###############################################################
#  Generated by:      Cadence Innovus 21.14-s109_1
#  OS:                Linux x86_64(Host ID caen-vnc-mi05.engin.umich.edu)
#  Generated on:      Thu Mar 30 18:29:03 2023
#  Design:            writeback_controller
#  Command:           write_lef_abstract /afs/umich.edu/class/eecs627/w23/groups/group4/CNN_LSTM/wb_controller/apr/wb_controller/data/writeback_controller.lef -specifyTopLayer 4 -stripePin -PGpinLayers 4
###############################################################

VERSION 5.8 ;

BUSBITCHARS "[]" ;
DIVIDERCHAR "/" ;

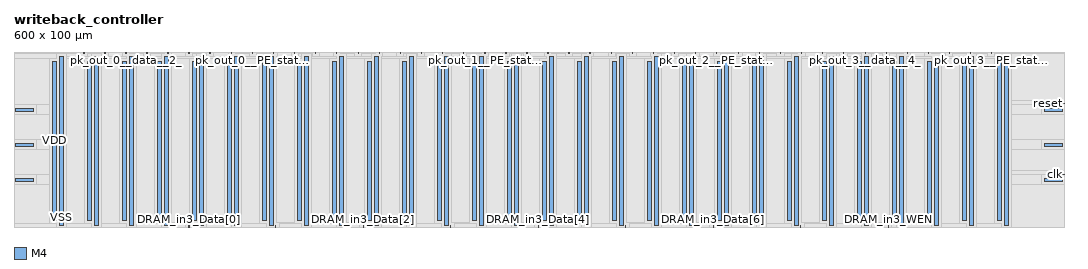
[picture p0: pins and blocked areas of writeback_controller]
MACRO writeback_controller
  CLASS BLOCK ;
  SIZE 600.000000 BY 100.000000 ;
  FOREIGN writeback_controller 0.000000 0.000000 ;
  ORIGIN 0 0 ;
  SYMMETRY X Y R90 ;
  PIN clk
    DIRECTION INPUT ;
    USE SIGNAL ;
    ANTENNAPARTIALMETALAREA 12.02 LAYER M4  ;
    ANTENNAPARTIALMETALSIDEAREA 0.1206 LAYER M4  ;
    ANTENNAMODEL OXIDE1 ;
    ANTENNAGATEAREA 1.2096 LAYER M4  ;
    ANTENNAMAXAREACAR 92.9835 LAYER M4  ;
    ANTENNAMAXSIDEAREACAR 0.93879 LAYER M4  ;
    ANTENNAMAXCUTCAR 2.38095 LAYER V4  ;
    PORT
      LAYER M4 ;
        RECT 599.400000 29.900000 600.000000 30.100000 ;
    END
  END clk
  PIN reset
    DIRECTION INPUT ;
    USE SIGNAL ;
    ANTENNAPARTIALMETALAREA 3.36 LAYER M4  ;
    ANTENNAPARTIALMETALSIDEAREA 0.0336 LAYER M4  ;
    ANTENNAMODEL OXIDE1 ;
    ANTENNAGATEAREA 0.2136 LAYER M4  ;
    ANTENNAMAXAREACAR 122.578 LAYER M4  ;
    ANTENNAMAXSIDEAREACAR 1.23081 LAYER M4  ;
    ANTENNAMAXCUTCAR 0.93633 LAYER V4  ;
    PORT
      LAYER M4 ;
        RECT 599.400000 70.300000 600.000000 70.500000 ;
    END
  END reset
  PIN DRAM_in3_WEN
    DIRECTION OUTPUT ;
    USE SIGNAL ;
    ANTENNADIFFAREA 2.112 LAYER M4  ;
    ANTENNAPARTIALMETALAREA 14.46 LAYER M4  ;
    ANTENNAPARTIALMETALSIDEAREA 0.1446 LAYER M4  ;
    PORT
      LAYER M4 ;
        RECT 499.500000 0.000000 499.700000 0.600000 ;
    END
  END DRAM_in3_WEN
  PIN DRAM_in3_Data[7]
    DIRECTION OUTPUT ;
    USE SIGNAL ;
    ANTENNADIFFAREA 3.348 LAYER M4  ;
    ANTENNAPARTIALMETALAREA 15.26 LAYER M4  ;
    ANTENNAPARTIALMETALSIDEAREA 0.1526 LAYER M4  ;
    PORT
      LAYER M4 ;
        RECT 449.500000 0.000000 449.700000 0.600000 ;
    END
  END DRAM_in3_Data[7]
  PIN DRAM_in3_Data[6]
    DIRECTION OUTPUT ;
    USE SIGNAL ;
    ANTENNADIFFAREA 3.348 LAYER M4  ;
    ANTENNAPARTIALMETALAREA 14.94 LAYER M4  ;
    ANTENNAPARTIALMETALSIDEAREA 0.1494 LAYER M4  ;
    PORT
      LAYER M4 ;
        RECT 399.500000 0.000000 399.700000 0.600000 ;
    END
  END DRAM_in3_Data[6]
  PIN DRAM_in3_Data[5]
    DIRECTION OUTPUT ;
    USE SIGNAL ;
    ANTENNADIFFAREA 2.112 LAYER M4  ;
    ANTENNAPARTIALMETALAREA 11.26 LAYER M4  ;
    ANTENNAPARTIALMETALSIDEAREA 0.1126 LAYER M4  ;
    PORT
      LAYER M4 ;
        RECT 349.500000 0.000000 349.700000 0.600000 ;
    END
  END DRAM_in3_Data[5]
  PIN DRAM_in3_Data[4]
    DIRECTION OUTPUT ;
    USE SIGNAL ;
    ANTENNADIFFAREA 2.112 LAYER M4  ;
    ANTENNAPARTIALMETALAREA 1.58 LAYER M4  ;
    ANTENNAPARTIALMETALSIDEAREA 0.0158 LAYER M4  ;
    PORT
      LAYER M4 ;
        RECT 299.500000 0.000000 299.700000 0.600000 ;
    END
  END DRAM_in3_Data[4]
  PIN DRAM_in3_Data[3]
    DIRECTION OUTPUT ;
    USE SIGNAL ;
    ANTENNADIFFAREA 2.112 LAYER M4  ;
    ANTENNAPARTIALMETALAREA 6.46 LAYER M4  ;
    ANTENNAPARTIALMETALSIDEAREA 0.0646 LAYER M4  ;
    PORT
      LAYER M4 ;
        RECT 249.500000 0.000000 249.700000 0.600000 ;
    END
  END DRAM_in3_Data[3]
  PIN DRAM_in3_Data[2]
    DIRECTION OUTPUT ;
    USE SIGNAL ;
    ANTENNADIFFAREA 2.112 LAYER M4  ;
    ANTENNAPARTIALMETALAREA 11.12 LAYER M4  ;
    ANTENNAPARTIALMETALSIDEAREA 0.1112 LAYER M4  ;
    PORT
      LAYER M4 ;
        RECT 199.500000 0.000000 199.700000 0.600000 ;
    END
  END DRAM_in3_Data[2]
  PIN DRAM_in3_Data[1]
    DIRECTION OUTPUT ;
    USE SIGNAL ;
    ANTENNADIFFAREA 2.112 LAYER M4  ;
    ANTENNAPARTIALMETALAREA 14.54 LAYER M4  ;
    ANTENNAPARTIALMETALSIDEAREA 0.1454 LAYER M4  ;
    PORT
      LAYER M4 ;
        RECT 149.500000 0.000000 149.700000 0.600000 ;
    END
  END DRAM_in3_Data[1]
  PIN DRAM_in3_Data[0]
    DIRECTION OUTPUT ;
    USE SIGNAL ;
    ANTENNADIFFAREA 2.112 LAYER M4  ;
    ANTENNAPARTIALMETALAREA 14.94 LAYER M4  ;
    ANTENNAPARTIALMETALSIDEAREA 0.1494 LAYER M4  ;
    PORT
      LAYER M4 ;
        RECT 99.900000 0.000000 100.100000 0.600000 ;
    END
  END DRAM_in3_Data[0]
  PIN pk_out_3__PE_state__2_
    DIRECTION INPUT ;
    USE SIGNAL ;
    ANTENNAPARTIALMETALAREA 2.3 LAYER M4  ;
    ANTENNAPARTIALMETALSIDEAREA 0.023 LAYER M4  ;
    ANTENNAMODEL OXIDE1 ;
    ANTENNAGATEAREA 0.0624 LAYER M4  ;
    ANTENNAMAXAREACAR 91.4599 LAYER M4  ;
    ANTENNAMAXSIDEAREACAR 0.930128 LAYER M4  ;
    ANTENNAMAXCUTCAR 3.20513 LAYER V4  ;
    PORT
      LAYER M4 ;
        RECT 558.300000 99.400000 558.500000 100.000000 ;
    END
  END pk_out_3__PE_state__2_
  PIN pk_out_3__PE_state__1_
    DIRECTION INPUT ;
    USE SIGNAL ;
    ANTENNAPARTIALMETALAREA 1.9 LAYER M4  ;
    ANTENNAPARTIALMETALSIDEAREA 0.019 LAYER M4  ;
    ANTENNAMODEL OXIDE1 ;
    ANTENNAGATEAREA 0.1632 LAYER M4  ;
    ANTENNAMAXAREACAR 21.9412 LAYER M4  ;
    ANTENNAMAXSIDEAREACAR 0.225613 LAYER M4  ;
    ANTENNAMAXCUTCAR 1.22549 LAYER V4  ;
    PORT
      LAYER M4 ;
        RECT 546.300000 99.400000 546.500000 100.000000 ;
    END
  END pk_out_3__PE_state__1_
  PIN pk_out_3__PE_state__0_
    DIRECTION INPUT ;
    USE SIGNAL ;
    ANTENNAPARTIALMETALAREA 2.06 LAYER M4  ;
    ANTENNAPARTIALMETALSIDEAREA 0.0206 LAYER M4  ;
    ANTENNAMODEL OXIDE1 ;
    ANTENNAGATEAREA 0.1632 LAYER M4  ;
    ANTENNAMAXAREACAR 26.7126 LAYER M4  ;
    ANTENNAMAXSIDEAREACAR 0.272794 LAYER M4  ;
    ANTENNAMAXCUTCAR 1.22549 LAYER V4  ;
    PORT
      LAYER M4 ;
        RECT 534.300000 99.400000 534.500000 100.000000 ;
    END
  END pk_out_3__PE_state__0_
  PIN pk_out_3__data__7_
    DIRECTION INPUT ;
    USE SIGNAL ;
    PORT
      LAYER M4 ;
        RECT 522.300000 99.400000 522.500000 100.000000 ;
    END
  END pk_out_3__data__7_
  PIN pk_out_3__data__6_
    DIRECTION INPUT ;
    USE SIGNAL ;
    PORT
      LAYER M4 ;
        RECT 510.300000 99.400000 510.500000 100.000000 ;
    END
  END pk_out_3__data__6_
  PIN pk_out_3__data__5_
    DIRECTION INPUT ;
    USE SIGNAL ;
    PORT
      LAYER M4 ;
        RECT 498.300000 99.400000 498.500000 100.000000 ;
    END
  END pk_out_3__data__5_
  PIN pk_out_3__data__4_
    DIRECTION INPUT ;
    USE SIGNAL ;
    PORT
      LAYER M4 ;
        RECT 486.300000 99.400000 486.500000 100.000000 ;
    END
  END pk_out_3__data__4_
  PIN pk_out_3__data__3_
    DIRECTION INPUT ;
    USE SIGNAL ;
    PORT
      LAYER M4 ;
        RECT 473.900000 99.400000 474.100000 100.000000 ;
    END
  END pk_out_3__data__3_
  PIN pk_out_3__data__2_
    DIRECTION INPUT ;
    USE SIGNAL ;
    PORT
      LAYER M4 ;
        RECT 461.900000 99.400000 462.100000 100.000000 ;
    END
  END pk_out_3__data__2_
  PIN pk_out_3__data__1_
    DIRECTION INPUT ;
    USE SIGNAL ;
    PORT
      LAYER M4 ;
        RECT 449.900000 99.400000 450.100000 100.000000 ;
    END
  END pk_out_3__data__1_
  PIN pk_out_3__data__0_
    DIRECTION INPUT ;
    USE SIGNAL ;
    PORT
      LAYER M4 ;
        RECT 437.900000 99.400000 438.100000 100.000000 ;
    END
  END pk_out_3__data__0_
  PIN pk_out_2__PE_state__2_
    DIRECTION INPUT ;
    USE SIGNAL ;
    ANTENNAPARTIALMETALAREA 2.54 LAYER M4  ;
    ANTENNAPARTIALMETALSIDEAREA 0.0254 LAYER M4  ;
    ANTENNAMODEL OXIDE1 ;
    ANTENNAGATEAREA 0.0624 LAYER M4  ;
    ANTENNAMAXAREACAR 105.562 LAYER M4  ;
    ANTENNAMAXSIDEAREACAR 1.07115 LAYER M4  ;
    ANTENNAMAXCUTCAR 3.20513 LAYER V4  ;
    PORT
      LAYER M4 ;
        RECT 425.900000 99.400000 426.100000 100.000000 ;
    END
  END pk_out_2__PE_state__2_
  PIN pk_out_2__PE_state__1_
    DIRECTION INPUT ;
    USE SIGNAL ;
    ANTENNAPARTIALMETALAREA 2.14 LAYER M4  ;
    ANTENNAPARTIALMETALSIDEAREA 0.0214 LAYER M4  ;
    ANTENNAMODEL OXIDE1 ;
    ANTENNAGATEAREA 0.1632 LAYER M4  ;
    ANTENNAMAXAREACAR 24.3922 LAYER M4  ;
    ANTENNAMAXSIDEAREACAR 0.250123 LAYER M4  ;
    ANTENNAMAXCUTCAR 1.22549 LAYER V4  ;
    PORT
      LAYER M4 ;
        RECT 413.900000 99.400000 414.100000 100.000000 ;
    END
  END pk_out_2__PE_state__1_
  PIN pk_out_2__PE_state__0_
    DIRECTION INPUT ;
    USE SIGNAL ;
    ANTENNAPARTIALMETALAREA 2.78 LAYER M4  ;
    ANTENNAPARTIALMETALSIDEAREA 0.0278 LAYER M4  ;
    ANTENNAMODEL OXIDE1 ;
    ANTENNAGATEAREA 0.1632 LAYER M4  ;
    ANTENNAMAXAREACAR 27.2028 LAYER M4  ;
    ANTENNAMAXSIDEAREACAR 0.277696 LAYER M4  ;
    ANTENNAMAXCUTCAR 1.22549 LAYER V4  ;
    PORT
      LAYER M4 ;
        RECT 401.500000 99.400000 401.700000 100.000000 ;
    END
  END pk_out_2__PE_state__0_
  PIN pk_out_2__data__7_
    DIRECTION INPUT ;
    USE SIGNAL ;
    PORT
      LAYER M4 ;
        RECT 389.500000 99.400000 389.700000 100.000000 ;
    END
  END pk_out_2__data__7_
  PIN pk_out_2__data__6_
    DIRECTION INPUT ;
    USE SIGNAL ;
    PORT
      LAYER M4 ;
        RECT 377.500000 99.400000 377.700000 100.000000 ;
    END
  END pk_out_2__data__6_
  PIN pk_out_2__data__5_
    DIRECTION INPUT ;
    USE SIGNAL ;
    PORT
      LAYER M4 ;
        RECT 365.500000 99.400000 365.700000 100.000000 ;
    END
  END pk_out_2__data__5_
  PIN pk_out_2__data__4_
    DIRECTION INPUT ;
    USE SIGNAL ;
    PORT
      LAYER M4 ;
        RECT 353.500000 99.400000 353.700000 100.000000 ;
    END
  END pk_out_2__data__4_
  PIN pk_out_2__data__3_
    DIRECTION INPUT ;
    USE SIGNAL ;
    PORT
      LAYER M4 ;
        RECT 341.500000 99.400000 341.700000 100.000000 ;
    END
  END pk_out_2__data__3_
  PIN pk_out_2__data__2_
    DIRECTION INPUT ;
    USE SIGNAL ;
    PORT
      LAYER M4 ;
        RECT 329.100000 99.400000 329.300000 100.000000 ;
    END
  END pk_out_2__data__2_
  PIN pk_out_2__data__1_
    DIRECTION INPUT ;
    USE SIGNAL ;
    PORT
      LAYER M4 ;
        RECT 317.100000 99.400000 317.300000 100.000000 ;
    END
  END pk_out_2__data__1_
  PIN pk_out_2__data__0_
    DIRECTION INPUT ;
    USE SIGNAL ;
    PORT
      LAYER M4 ;
        RECT 305.100000 99.400000 305.300000 100.000000 ;
    END
  END pk_out_2__data__0_
  PIN pk_out_1__PE_state__2_
    DIRECTION INPUT ;
    USE SIGNAL ;
    ANTENNAPARTIALMETALAREA 2.3 LAYER M4  ;
    ANTENNAPARTIALMETALSIDEAREA 0.023 LAYER M4  ;
    ANTENNAMODEL OXIDE1 ;
    ANTENNAGATEAREA 0.0624 LAYER M4  ;
    ANTENNAMAXAREACAR 69.6651 LAYER M4  ;
    ANTENNAMAXSIDEAREACAR 0.712179 LAYER M4  ;
    ANTENNAMAXCUTCAR 3.20513 LAYER V4  ;
    PORT
      LAYER M4 ;
        RECT 293.100000 99.400000 293.300000 100.000000 ;
    END
  END pk_out_1__PE_state__2_
  PIN pk_out_1__PE_state__1_
    DIRECTION INPUT ;
    USE SIGNAL ;
    ANTENNAPARTIALMETALAREA 2.22 LAYER M4  ;
    ANTENNAPARTIALMETALSIDEAREA 0.0222 LAYER M4  ;
    ANTENNAMODEL OXIDE1 ;
    ANTENNAGATEAREA 0.1632 LAYER M4  ;
    ANTENNAMAXAREACAR 21.451 LAYER M4  ;
    ANTENNAMAXSIDEAREACAR 0.220711 LAYER M4  ;
    ANTENNAMAXCUTCAR 1.22549 LAYER V4  ;
    PORT
      LAYER M4 ;
        RECT 281.100000 99.400000 281.300000 100.000000 ;
    END
  END pk_out_1__PE_state__1_
  PIN pk_out_1__PE_state__0_
    DIRECTION INPUT ;
    USE SIGNAL ;
    ANTENNAPARTIALMETALAREA 2.3 LAYER M4  ;
    ANTENNAPARTIALMETALSIDEAREA 0.023 LAYER M4  ;
    ANTENNAMODEL OXIDE1 ;
    ANTENNAGATEAREA 0.1632 LAYER M4  ;
    ANTENNAMAXAREACAR 34.5558 LAYER M4  ;
    ANTENNAMAXSIDEAREACAR 0.351225 LAYER M4  ;
    ANTENNAMAXCUTCAR 1.22549 LAYER V4  ;
    PORT
      LAYER M4 ;
        RECT 269.100000 99.400000 269.300000 100.000000 ;
    END
  END pk_out_1__PE_state__0_
  PIN pk_out_1__data__7_
    DIRECTION INPUT ;
    USE SIGNAL ;
    ANTENNAPARTIALMETALAREA 2.26 LAYER M4  ;
    ANTENNAPARTIALMETALSIDEAREA 0.023 LAYER M4  ;
    ANTENNAMODEL OXIDE1 ;
    ANTENNAGATEAREA 0.0888 LAYER M4  ;
    ANTENNAMAXAREACAR 38.7072 LAYER M4  ;
    ANTENNAMAXSIDEAREACAR 0.403829 LAYER M4  ;
    ANTENNAMAXCUTCAR 2.25225 LAYER V4  ;
    PORT
      LAYER M4 ;
        RECT 256.700000 99.400000 256.900000 100.000000 ;
    END
  END pk_out_1__data__7_
  PIN pk_out_1__data__6_
    DIRECTION INPUT ;
    USE SIGNAL ;
    ANTENNAPARTIALMETALAREA 2.34 LAYER M4  ;
    ANTENNAPARTIALMETALSIDEAREA 0.0238 LAYER M4  ;
    ANTENNAMODEL OXIDE1 ;
    ANTENNAGATEAREA 0.0888 LAYER M4  ;
    ANTENNAMAXAREACAR 43.2117 LAYER M4  ;
    ANTENNAMAXSIDEAREACAR 0.448874 LAYER M4  ;
    ANTENNAMAXCUTCAR 2.25225 LAYER V4  ;
    PORT
      LAYER M4 ;
        RECT 244.700000 99.400000 244.900000 100.000000 ;
    END
  END pk_out_1__data__6_
  PIN pk_out_1__data__5_
    DIRECTION INPUT ;
    USE SIGNAL ;
    ANTENNAPARTIALMETALAREA 2.34 LAYER M4  ;
    ANTENNAPARTIALMETALSIDEAREA 0.0238 LAYER M4  ;
    ANTENNAMODEL OXIDE1 ;
    ANTENNAGATEAREA 0.0888 LAYER M4  ;
    ANTENNAMAXAREACAR 41.4099 LAYER M4  ;
    ANTENNAMAXSIDEAREACAR 0.430856 LAYER M4  ;
    ANTENNAMAXCUTCAR 2.25225 LAYER V4  ;
    PORT
      LAYER M4 ;
        RECT 232.700000 99.400000 232.900000 100.000000 ;
    END
  END pk_out_1__data__5_
  PIN pk_out_1__data__4_
    DIRECTION INPUT ;
    USE SIGNAL ;
    ANTENNAPARTIALMETALAREA 2.26 LAYER M4  ;
    ANTENNAPARTIALMETALSIDEAREA 0.023 LAYER M4  ;
    ANTENNAMODEL OXIDE1 ;
    ANTENNAGATEAREA 0.0888 LAYER M4  ;
    ANTENNAMAXAREACAR 41.4099 LAYER M4  ;
    ANTENNAMAXSIDEAREACAR 0.430856 LAYER M4  ;
    ANTENNAMAXCUTCAR 2.25225 LAYER V4  ;
    PORT
      LAYER M4 ;
        RECT 220.700000 99.400000 220.900000 100.000000 ;
    END
  END pk_out_1__data__4_
  PIN pk_out_1__data__3_
    DIRECTION INPUT ;
    USE SIGNAL ;
    ANTENNAPARTIALMETALAREA 2.42 LAYER M4  ;
    ANTENNAPARTIALMETALSIDEAREA 0.0246 LAYER M4  ;
    ANTENNAMODEL OXIDE1 ;
    ANTENNAGATEAREA 0.0888 LAYER M4  ;
    ANTENNAMAXAREACAR 42.3108 LAYER M4  ;
    ANTENNAMAXSIDEAREACAR 0.439865 LAYER M4  ;
    ANTENNAMAXCUTCAR 2.25225 LAYER V4  ;
    PORT
      LAYER M4 ;
        RECT 208.700000 99.400000 208.900000 100.000000 ;
    END
  END pk_out_1__data__3_
  PIN pk_out_1__data__2_
    DIRECTION INPUT ;
    USE SIGNAL ;
    ANTENNAPARTIALMETALAREA 1.62 LAYER M4  ;
    ANTENNAPARTIALMETALSIDEAREA 0.0166 LAYER M4  ;
    ANTENNAMODEL OXIDE1 ;
    ANTENNAGATEAREA 0.0888 LAYER M4  ;
    ANTENNAMAXAREACAR 31.5 LAYER M4  ;
    ANTENNAMAXSIDEAREACAR 0.331757 LAYER M4  ;
    ANTENNAMAXCUTCAR 2.25225 LAYER V4  ;
    PORT
      LAYER M4 ;
        RECT 196.700000 99.400000 196.900000 100.000000 ;
    END
  END pk_out_1__data__2_
  PIN pk_out_1__data__1_
    DIRECTION INPUT ;
    USE SIGNAL ;
    ANTENNAPARTIALMETALAREA 3.06 LAYER M4  ;
    ANTENNAPARTIALMETALSIDEAREA 0.031 LAYER M4  ;
    ANTENNAMODEL OXIDE1 ;
    ANTENNAGATEAREA 0.0888 LAYER M4  ;
    ANTENNAMAXAREACAR 67.536 LAYER M4  ;
    ANTENNAMAXSIDEAREACAR 0.692117 LAYER M4  ;
    ANTENNAMAXCUTCAR 2.25225 LAYER V4  ;
    PORT
      LAYER M4 ;
        RECT 184.300000 99.400000 184.500000 100.000000 ;
    END
  END pk_out_1__data__1_
  PIN pk_out_1__data__0_
    DIRECTION INPUT ;
    USE SIGNAL ;
    ANTENNAPARTIALMETALAREA 2.34 LAYER M4  ;
    ANTENNAPARTIALMETALSIDEAREA 0.0238 LAYER M4  ;
    ANTENNAMODEL OXIDE1 ;
    ANTENNAGATEAREA 0.0888 LAYER M4  ;
    ANTENNAMAXAREACAR 31.5 LAYER M4  ;
    ANTENNAMAXSIDEAREACAR 0.331757 LAYER M4  ;
    ANTENNAMAXCUTCAR 2.25225 LAYER V4  ;
    PORT
      LAYER M4 ;
        RECT 172.300000 99.400000 172.500000 100.000000 ;
    END
  END pk_out_1__data__0_
  PIN pk_out_0__PE_state__2_
    DIRECTION INPUT ;
    USE SIGNAL ;
    ANTENNAPARTIALMETALAREA 2.14 LAYER M4  ;
    ANTENNAPARTIALMETALSIDEAREA 0.0214 LAYER M4  ;
    ANTENNAMODEL OXIDE1 ;
    ANTENNAGATEAREA 0.6168 LAYER M4  ;
    ANTENNAMAXAREACAR 6.89559 LAYER M4  ;
    ANTENNAMAXSIDEAREACAR 0.070655 LAYER M4  ;
    ANTENNAMAXCUTCAR 0.259403 LAYER V4  ;
    PORT
      LAYER M4 ;
        RECT 160.300000 99.400000 160.500000 100.000000 ;
    END
  END pk_out_0__PE_state__2_
  PIN pk_out_0__PE_state__1_
    DIRECTION INPUT ;
    USE SIGNAL ;
    ANTENNAPARTIALMETALAREA 2.46 LAYER M4  ;
    ANTENNAPARTIALMETALSIDEAREA 0.0246 LAYER M4  ;
    ANTENNAMODEL OXIDE1 ;
    ANTENNAGATEAREA 0.1488 LAYER M4  ;
    ANTENNAMAXAREACAR 23.369 LAYER M4  ;
    ANTENNAMAXSIDEAREACAR 0.238038 LAYER M4  ;
    ANTENNAMAXCUTCAR 1.6129 LAYER V4  ;
    PORT
      LAYER M4 ;
        RECT 148.300000 99.400000 148.500000 100.000000 ;
    END
  END pk_out_0__PE_state__1_
  PIN pk_out_0__PE_state__0_
    DIRECTION INPUT ;
    USE SIGNAL ;
    ANTENNAPARTIALMETALAREA 2.22 LAYER M4  ;
    ANTENNAPARTIALMETALSIDEAREA 0.0222 LAYER M4  ;
    ANTENNAMODEL OXIDE1 ;
    ANTENNAGATEAREA 0.1488 LAYER M4  ;
    ANTENNAMAXAREACAR 31.5316 LAYER M4  ;
    ANTENNAMAXSIDEAREACAR 0.321237 LAYER M4  ;
    ANTENNAMAXCUTCAR 1.34409 LAYER V4  ;
    PORT
      LAYER M4 ;
        RECT 136.300000 99.400000 136.500000 100.000000 ;
    END
  END pk_out_0__PE_state__0_
  PIN pk_out_0__data__7_
    DIRECTION INPUT ;
    USE SIGNAL ;
    ANTENNAPARTIALMETALAREA 4.7 LAYER M4  ;
    ANTENNAPARTIALMETALSIDEAREA 0.047 LAYER M4  ;
    ANTENNAMODEL OXIDE1 ;
    ANTENNAGATEAREA 0.1728 LAYER M4  ;
    ANTENNAMAXAREACAR 91.4722 LAYER M4  ;
    ANTENNAMAXSIDEAREACAR 0.920718 LAYER M4  ;
    ANTENNAMAXCUTCAR 1.15741 LAYER V4  ;
    PORT
      LAYER M4 ;
        RECT 124.300000 99.400000 124.500000 100.000000 ;
    END
  END pk_out_0__data__7_
  PIN pk_out_0__data__6_
    DIRECTION INPUT ;
    USE SIGNAL ;
    ANTENNAPARTIALMETALAREA 1.7 LAYER M4  ;
    ANTENNAPARTIALMETALSIDEAREA 0.0174 LAYER M4  ;
    ANTENNAMODEL OXIDE1 ;
    ANTENNAGATEAREA 0.1728 LAYER M4  ;
    ANTENNAMAXAREACAR 15.7778 LAYER M4  ;
    ANTENNAMAXSIDEAREACAR 0.166088 LAYER M4  ;
    ANTENNAMAXCUTCAR 1.15741 LAYER V4  ;
    PORT
      LAYER M4 ;
        RECT 111.900000 99.400000 112.100000 100.000000 ;
    END
  END pk_out_0__data__6_
  PIN pk_out_0__data__5_
    DIRECTION INPUT ;
    USE SIGNAL ;
    ANTENNAPARTIALMETALAREA 2.38 LAYER M4  ;
    ANTENNAPARTIALMETALSIDEAREA 0.0238 LAYER M4  ;
    ANTENNAMODEL OXIDE1 ;
    ANTENNAGATEAREA 0.1728 LAYER M4  ;
    ANTENNAMAXAREACAR 97.0278 LAYER M4  ;
    ANTENNAMAXSIDEAREACAR 0.976273 LAYER M4  ;
    ANTENNAMAXCUTCAR 1.15741 LAYER V4  ;
    PORT
      LAYER M4 ;
        RECT 99.900000 99.400000 100.100000 100.000000 ;
    END
  END pk_out_0__data__5_
  PIN pk_out_0__data__4_
    DIRECTION INPUT ;
    USE SIGNAL ;
    ANTENNAPARTIALMETALAREA 4.3 LAYER M4  ;
    ANTENNAPARTIALMETALSIDEAREA 0.043 LAYER M4  ;
    ANTENNAMODEL OXIDE1 ;
    ANTENNAGATEAREA 0.1728 LAYER M4  ;
    ANTENNAMAXAREACAR 132.676 LAYER M4  ;
    ANTENNAMAXSIDEAREACAR 1.33275 LAYER M4  ;
    ANTENNAMAXCUTCAR 1.15741 LAYER V4  ;
    PORT
      LAYER M4 ;
        RECT 87.900000 99.400000 88.100000 100.000000 ;
    END
  END pk_out_0__data__4_
  PIN pk_out_0__data__3_
    DIRECTION INPUT ;
    USE SIGNAL ;
    ANTENNAPARTIALMETALAREA 2.54 LAYER M4  ;
    ANTENNAPARTIALMETALSIDEAREA 0.0254 LAYER M4  ;
    ANTENNAMODEL OXIDE1 ;
    ANTENNAGATEAREA 0.1728 LAYER M4  ;
    ANTENNAMAXAREACAR 120.639 LAYER M4  ;
    ANTENNAMAXSIDEAREACAR 1.21238 LAYER M4  ;
    ANTENNAMAXCUTCAR 1.15741 LAYER V4  ;
    PORT
      LAYER M4 ;
        RECT 75.900000 99.400000 76.100000 100.000000 ;
    END
  END pk_out_0__data__3_
  PIN pk_out_0__data__2_
    DIRECTION INPUT ;
    USE SIGNAL ;
    ANTENNAPARTIALMETALAREA 3.82 LAYER M4  ;
    ANTENNAPARTIALMETALSIDEAREA 0.0382 LAYER M4  ;
    ANTENNAMODEL OXIDE1 ;
    ANTENNAGATEAREA 0.1728 LAYER M4  ;
    ANTENNAMAXAREACAR 141.935 LAYER M4  ;
    ANTENNAMAXSIDEAREACAR 1.42535 LAYER M4  ;
    ANTENNAMAXCUTCAR 1.15741 LAYER V4  ;
    PORT
      LAYER M4 ;
        RECT 63.900000 99.400000 64.100000 100.000000 ;
    END
  END pk_out_0__data__2_
  PIN pk_out_0__data__1_
    DIRECTION INPUT ;
    USE SIGNAL ;
    ANTENNAPARTIALMETALAREA 2.86 LAYER M4  ;
    ANTENNAPARTIALMETALSIDEAREA 0.0286 LAYER M4  ;
    ANTENNAMODEL OXIDE1 ;
    ANTENNAGATEAREA 0.1728 LAYER M4  ;
    ANTENNAMAXAREACAR 136.843 LAYER M4  ;
    ANTENNAMAXSIDEAREACAR 1.37442 LAYER M4  ;
    ANTENNAMAXCUTCAR 1.15741 LAYER V4  ;
    PORT
      LAYER M4 ;
        RECT 51.900000 99.400000 52.100000 100.000000 ;
    END
  END pk_out_0__data__1_
  PIN pk_out_0__data__0_
    DIRECTION INPUT ;
    USE SIGNAL ;
    ANTENNAPARTIALMETALAREA 3.18 LAYER M4  ;
    ANTENNAPARTIALMETALSIDEAREA 0.0318 LAYER M4  ;
    ANTENNAMODEL OXIDE1 ;
    ANTENNAGATEAREA 0.1728 LAYER M4  ;
    ANTENNAMAXAREACAR 142.861 LAYER M4  ;
    ANTENNAMAXSIDEAREACAR 1.43461 LAYER M4  ;
    ANTENNAMAXCUTCAR 1.15741 LAYER V4  ;
    PORT
      LAYER M4 ;
        RECT 39.900000 99.400000 40.100000 100.000000 ;
    END
  END pk_out_0__data__0_
  PIN VSS
    DIRECTION INOUT ;
    USE GROUND ;

# P/G power stripe data as pin
    PORT
      LAYER M4 ;
        RECT 26.000000 1.000000 28.000000 97.400000 ;
        RECT 46.000000 1.000000 48.000000 97.400000 ;
        RECT 66.000000 1.000000 68.000000 97.400000 ;
        RECT 86.000000 1.000000 88.000000 97.400000 ;
        RECT 106.000000 1.000000 108.000000 97.400000 ;
        RECT 126.000000 1.000000 128.000000 97.400000 ;
        RECT 146.000000 1.000000 148.000000 97.400000 ;
        RECT 186.000000 1.000000 188.000000 97.400000 ;
        RECT 166.000000 1.000000 168.000000 97.400000 ;
        RECT 206.000000 1.000000 208.000000 97.400000 ;
        RECT 226.000000 1.000000 228.000000 97.400000 ;
        RECT 246.000000 1.000000 248.000000 97.400000 ;
        RECT 266.000000 1.000000 268.000000 97.400000 ;
        RECT 286.000000 1.000000 288.000000 97.400000 ;
        RECT 306.000000 1.000000 308.000000 97.400000 ;
        RECT 326.000000 1.000000 328.000000 97.400000 ;
        RECT 346.000000 1.000000 348.000000 97.400000 ;
        RECT 366.000000 1.000000 368.000000 97.400000 ;
        RECT 386.000000 1.000000 388.000000 97.400000 ;
        RECT 406.000000 1.000000 408.000000 97.400000 ;
        RECT 426.000000 1.000000 428.000000 97.400000 ;
        RECT 446.000000 1.000000 448.000000 97.400000 ;
        RECT 486.000000 1.000000 488.000000 97.400000 ;
        RECT 466.000000 1.000000 468.000000 97.400000 ;
        RECT 506.000000 1.000000 508.000000 97.400000 ;
        RECT 526.000000 1.000000 528.000000 97.400000 ;
        RECT 546.000000 1.000000 548.000000 97.400000 ;
        RECT 566.000000 1.000000 568.000000 97.400000 ;
        RECT 1.000000 26.000000 10.880000 28.000000 ;
        RECT 1.000000 46.000000 10.880000 48.000000 ;
        RECT 589.120000 26.000000 599.000000 28.000000 ;
        RECT 589.120000 46.000000 599.000000 48.000000 ;
        RECT 1.000000 66.000000 10.880000 68.000000 ;
        RECT 589.120000 66.000000 599.000000 68.000000 ;
    END
# end of P/G power stripe data as pin

  END VSS
  PIN VDD
    DIRECTION INOUT ;
    USE POWER ;

# P/G power stripe data as pin
    PORT
      LAYER M4 ;
        RECT 22.000000 4.000000 24.000000 94.400000 ;
        RECT 62.000000 4.000000 64.000000 94.400000 ;
        RECT 42.000000 4.000000 44.000000 94.400000 ;
        RECT 102.000000 4.000000 104.000000 94.400000 ;
        RECT 82.000000 4.000000 84.000000 94.400000 ;
        RECT 142.000000 4.000000 144.000000 94.400000 ;
        RECT 122.000000 4.000000 124.000000 94.400000 ;
        RECT 182.000000 4.000000 184.000000 94.400000 ;
        RECT 162.000000 4.000000 164.000000 94.400000 ;
        RECT 222.000000 4.000000 224.000000 94.400000 ;
        RECT 202.000000 4.000000 204.000000 94.400000 ;
        RECT 262.000000 4.000000 264.000000 94.400000 ;
        RECT 242.000000 4.000000 244.000000 94.400000 ;
        RECT 282.000000 4.000000 284.000000 94.400000 ;
        RECT 322.000000 4.000000 324.000000 94.400000 ;
        RECT 302.000000 4.000000 304.000000 94.400000 ;
        RECT 362.000000 4.000000 364.000000 94.400000 ;
        RECT 342.000000 4.000000 344.000000 94.400000 ;
        RECT 402.000000 4.000000 404.000000 94.400000 ;
        RECT 382.000000 4.000000 384.000000 94.400000 ;
        RECT 442.000000 4.000000 444.000000 94.400000 ;
        RECT 422.000000 4.000000 424.000000 94.400000 ;
        RECT 482.000000 4.000000 484.000000 94.400000 ;
        RECT 462.000000 4.000000 464.000000 94.400000 ;
        RECT 502.000000 4.000000 504.000000 94.400000 ;
        RECT 522.000000 4.000000 524.000000 94.400000 ;
        RECT 562.000000 4.000000 564.000000 94.400000 ;
        RECT 542.000000 4.000000 544.000000 94.400000 ;
    END
# end of P/G power stripe data as pin

  END VDD
  OBS
    LAYER M1 ;
      RECT 0.000000 0.000000 600.000000 100.000000 ;
    LAYER M2 ;
      RECT 0.000000 0.000000 600.000000 100.000000 ;
    LAYER M3 ;
      RECT 0.000000 0.000000 600.000000 100.000000 ;
    LAYER M4 ;
      RECT 560.420000 99.320000 600.000000 100.000000 ;
      RECT 548.420000 99.320000 556.380000 100.000000 ;
      RECT 536.420000 99.320000 544.380000 100.000000 ;
      RECT 524.420000 99.320000 532.380000 100.000000 ;
      RECT 500.420000 99.320000 508.380000 100.000000 ;
      RECT 488.420000 99.320000 496.380000 100.000000 ;
      RECT 476.020000 99.320000 484.380000 100.000000 ;
      RECT 464.020000 99.320000 471.980000 100.000000 ;
      RECT 440.020000 99.320000 447.980000 100.000000 ;
      RECT 428.020000 99.320000 435.980000 100.000000 ;
      RECT 403.620000 99.320000 411.980000 100.000000 ;
      RECT 379.620000 99.320000 387.580000 100.000000 ;
      RECT 367.620000 99.320000 375.580000 100.000000 ;
      RECT 343.620000 99.320000 351.580000 100.000000 ;
      RECT 319.220000 99.320000 327.180000 100.000000 ;
      RECT 307.220000 99.320000 315.180000 100.000000 ;
      RECT 283.220000 99.320000 291.180000 100.000000 ;
      RECT 258.820000 99.320000 267.180000 100.000000 ;
      RECT 246.820000 99.320000 254.780000 100.000000 ;
      RECT 222.820000 99.320000 230.780000 100.000000 ;
      RECT 198.820000 99.320000 206.780000 100.000000 ;
      RECT 186.420000 99.320000 194.780000 100.000000 ;
      RECT 162.420000 99.320000 170.380000 100.000000 ;
      RECT 138.420000 99.320000 146.380000 100.000000 ;
      RECT 126.420000 99.320000 134.380000 100.000000 ;
      RECT 102.020000 99.320000 109.980000 100.000000 ;
      RECT 78.020000 99.320000 85.980000 100.000000 ;
      RECT 66.020000 99.320000 73.980000 100.000000 ;
      RECT 42.020000 99.320000 49.980000 100.000000 ;
      RECT 0.000000 99.320000 37.980000 100.000000 ;
      RECT 560.420000 97.480000 564.080000 99.320000 ;
      RECT 549.920000 97.480000 556.380000 99.320000 ;
      RECT 536.420000 97.480000 544.080000 99.320000 ;
      RECT 529.920000 97.480000 532.380000 99.320000 ;
      RECT 512.420000 97.480000 520.380000 100.000000 ;
      RECT 500.420000 97.480000 504.080000 99.320000 ;
      RECT 489.920000 97.480000 496.380000 99.320000 ;
      RECT 476.020000 97.480000 484.080000 99.320000 ;
      RECT 469.920000 97.480000 471.980000 99.320000 ;
      RECT 464.020000 97.480000 464.080000 99.320000 ;
      RECT 452.020000 97.480000 459.980000 100.000000 ;
      RECT 440.020000 97.480000 444.080000 99.320000 ;
      RECT 429.920000 97.480000 435.980000 99.320000 ;
      RECT 416.020000 97.480000 423.980000 100.000000 ;
      RECT 409.920000 97.480000 411.980000 99.320000 ;
      RECT 403.620000 97.480000 404.080000 99.320000 ;
      RECT 391.620000 97.480000 399.580000 100.000000 ;
      RECT 379.620000 97.480000 384.080000 99.320000 ;
      RECT 369.920000 97.480000 375.580000 99.320000 ;
      RECT 355.620000 97.480000 363.580000 100.000000 ;
      RECT 349.920000 97.480000 351.580000 99.320000 ;
      RECT 343.620000 97.480000 344.080000 99.320000 ;
      RECT 331.220000 97.480000 339.580000 100.000000 ;
      RECT 319.220000 97.480000 324.080000 99.320000 ;
      RECT 309.920000 97.480000 315.180000 99.320000 ;
      RECT 295.220000 97.480000 303.180000 100.000000 ;
      RECT 289.920000 97.480000 291.180000 99.320000 ;
      RECT 283.220000 97.480000 284.080000 99.320000 ;
      RECT 271.220000 97.480000 279.180000 100.000000 ;
      RECT 258.820000 97.480000 264.080000 99.320000 ;
      RECT 249.920000 97.480000 254.780000 99.320000 ;
      RECT 234.820000 97.480000 242.780000 100.000000 ;
      RECT 229.920000 97.480000 230.780000 99.320000 ;
      RECT 222.820000 97.480000 224.080000 99.320000 ;
      RECT 210.820000 97.480000 218.780000 100.000000 ;
      RECT 198.820000 97.480000 204.080000 99.320000 ;
      RECT 189.920000 97.480000 194.780000 99.320000 ;
      RECT 174.420000 97.480000 182.380000 100.000000 ;
      RECT 169.920000 97.480000 170.380000 99.320000 ;
      RECT 162.420000 97.480000 164.080000 99.320000 ;
      RECT 150.420000 97.480000 158.380000 100.000000 ;
      RECT 138.420000 97.480000 144.080000 99.320000 ;
      RECT 129.920000 97.480000 134.380000 99.320000 ;
      RECT 114.020000 97.480000 122.380000 100.000000 ;
      RECT 109.920000 97.480000 109.980000 99.320000 ;
      RECT 102.020000 97.480000 104.080000 99.320000 ;
      RECT 90.020000 97.480000 97.980000 100.000000 ;
      RECT 78.020000 97.480000 84.080000 99.320000 ;
      RECT 69.920000 97.480000 73.980000 99.320000 ;
      RECT 54.020000 97.480000 61.980000 100.000000 ;
      RECT 49.920000 97.480000 49.980000 99.320000 ;
      RECT 42.020000 97.480000 44.080000 99.320000 ;
      RECT 29.920000 97.480000 37.980000 99.320000 ;
      RECT 549.920000 96.320000 564.080000 97.480000 ;
      RECT 529.920000 96.320000 544.080000 97.480000 ;
      RECT 509.920000 96.320000 524.080000 97.480000 ;
      RECT 489.920000 96.320000 504.080000 97.480000 ;
      RECT 469.920000 96.320000 484.080000 97.480000 ;
      RECT 449.920000 96.320000 464.080000 97.480000 ;
      RECT 429.920000 96.320000 444.080000 97.480000 ;
      RECT 409.920000 96.320000 424.080000 97.480000 ;
      RECT 389.920000 96.320000 404.080000 97.480000 ;
      RECT 369.920000 96.320000 384.080000 97.480000 ;
      RECT 349.920000 96.320000 364.080000 97.480000 ;
      RECT 329.920000 96.320000 344.080000 97.480000 ;
      RECT 309.920000 96.320000 324.080000 97.480000 ;
      RECT 289.920000 96.320000 304.080000 97.480000 ;
      RECT 269.920000 96.320000 284.080000 97.480000 ;
      RECT 249.920000 96.320000 264.080000 97.480000 ;
      RECT 229.920000 96.320000 244.080000 97.480000 ;
      RECT 209.920000 96.320000 224.080000 97.480000 ;
      RECT 189.920000 96.320000 204.080000 97.480000 ;
      RECT 169.920000 96.320000 184.080000 97.480000 ;
      RECT 149.920000 96.320000 164.080000 97.480000 ;
      RECT 129.920000 96.320000 144.080000 97.480000 ;
      RECT 109.920000 96.320000 124.080000 97.480000 ;
      RECT 89.920000 96.320000 104.080000 97.480000 ;
      RECT 69.920000 96.320000 84.080000 97.480000 ;
      RECT 49.920000 96.320000 64.080000 97.480000 ;
      RECT 29.920000 96.320000 44.080000 97.480000 ;
      RECT 0.000000 96.320000 24.080000 99.320000 ;
      RECT 569.920000 72.420000 600.000000 99.320000 ;
      RECT 569.920000 69.920000 597.480000 72.420000 ;
      RECT 0.000000 69.920000 20.080000 96.320000 ;
      RECT 569.920000 64.080000 587.200000 69.920000 ;
      RECT 12.800000 64.080000 20.080000 69.920000 ;
      RECT 569.920000 49.920000 600.000000 64.080000 ;
      RECT 0.000000 49.920000 20.080000 64.080000 ;
      RECT 569.920000 44.080000 587.200000 49.920000 ;
      RECT 12.800000 44.080000 20.080000 49.920000 ;
      RECT 569.920000 32.020000 600.000000 44.080000 ;
      RECT 569.920000 29.920000 597.480000 32.020000 ;
      RECT 0.000000 29.920000 20.080000 44.080000 ;
      RECT 569.920000 24.080000 587.200000 29.920000 ;
      RECT 12.800000 24.080000 20.080000 29.920000 ;
      RECT 489.920000 2.520000 500.080000 96.320000 ;
      RECT 449.920000 2.520000 460.080000 96.320000 ;
      RECT 389.920000 2.520000 400.080000 96.320000 ;
      RECT 349.920000 2.520000 360.080000 96.320000 ;
      RECT 289.920000 2.520000 300.080000 96.320000 ;
      RECT 249.920000 2.520000 260.080000 96.320000 ;
      RECT 189.920000 2.520000 200.080000 96.320000 ;
      RECT 149.920000 2.520000 160.080000 96.320000 ;
      RECT 89.920000 2.520000 100.080000 96.320000 ;
      RECT 549.920000 2.080000 560.080000 96.320000 ;
      RECT 529.920000 2.080000 540.080000 96.320000 ;
      RECT 509.920000 2.080000 520.080000 96.320000 ;
      RECT 469.920000 2.080000 480.080000 96.320000 ;
      RECT 451.620000 2.080000 460.080000 2.520000 ;
      RECT 429.920000 2.080000 440.080000 96.320000 ;
      RECT 409.920000 2.080000 420.080000 96.320000 ;
      RECT 369.920000 2.080000 380.080000 96.320000 ;
      RECT 351.620000 2.080000 360.080000 2.520000 ;
      RECT 329.920000 2.080000 340.080000 96.320000 ;
      RECT 309.920000 2.080000 320.080000 96.320000 ;
      RECT 269.920000 2.080000 280.080000 96.320000 ;
      RECT 251.620000 2.080000 260.080000 2.520000 ;
      RECT 229.920000 2.080000 240.080000 96.320000 ;
      RECT 209.920000 2.080000 220.080000 96.320000 ;
      RECT 169.920000 2.080000 180.080000 96.320000 ;
      RECT 151.620000 2.080000 160.080000 2.520000 ;
      RECT 129.920000 2.080000 140.080000 96.320000 ;
      RECT 109.920000 2.080000 120.080000 96.320000 ;
      RECT 69.920000 2.080000 80.080000 96.320000 ;
      RECT 49.920000 2.080000 60.080000 96.320000 ;
      RECT 29.920000 2.080000 40.080000 96.320000 ;
      RECT 0.000000 2.080000 20.080000 24.080000 ;
      RECT 569.920000 0.000000 600.000000 24.080000 ;
      RECT 549.920000 0.000000 564.080000 2.080000 ;
      RECT 529.920000 0.000000 544.080000 2.080000 ;
      RECT 509.920000 0.000000 524.080000 2.080000 ;
      RECT 501.620000 0.000000 504.080000 2.080000 ;
      RECT 489.920000 0.000000 497.580000 2.520000 ;
      RECT 469.920000 0.000000 484.080000 2.080000 ;
      RECT 451.620000 0.000000 464.080000 2.080000 ;
      RECT 429.920000 0.000000 444.080000 2.080000 ;
      RECT 409.920000 0.000000 424.080000 2.080000 ;
      RECT 401.620000 0.000000 404.080000 2.080000 ;
      RECT 389.920000 0.000000 397.580000 2.520000 ;
      RECT 369.920000 0.000000 384.080000 2.080000 ;
      RECT 351.620000 0.000000 364.080000 2.080000 ;
      RECT 329.920000 0.000000 344.080000 2.080000 ;
      RECT 309.920000 0.000000 324.080000 2.080000 ;
      RECT 301.620000 0.000000 304.080000 2.080000 ;
      RECT 289.920000 0.000000 297.580000 2.520000 ;
      RECT 269.920000 0.000000 284.080000 2.080000 ;
      RECT 251.620000 0.000000 264.080000 2.080000 ;
      RECT 229.920000 0.000000 244.080000 2.080000 ;
      RECT 209.920000 0.000000 224.080000 2.080000 ;
      RECT 201.620000 0.000000 204.080000 2.080000 ;
      RECT 189.920000 0.000000 197.580000 2.520000 ;
      RECT 169.920000 0.000000 184.080000 2.080000 ;
      RECT 151.620000 0.000000 164.080000 2.080000 ;
      RECT 129.920000 0.000000 144.080000 2.080000 ;
      RECT 109.920000 0.000000 124.080000 2.080000 ;
      RECT 102.020000 0.000000 104.080000 2.080000 ;
      RECT 89.920000 0.000000 97.980000 2.520000 ;
      RECT 69.920000 0.000000 84.080000 2.080000 ;
      RECT 49.920000 0.000000 64.080000 2.080000 ;
      RECT 29.920000 0.000000 44.080000 2.080000 ;
      RECT 0.000000 0.000000 24.080000 2.080000 ;
  END
END writeback_controller

END LIBRARY
